VERSION 5.7 ;
  NOWIREEXTENSIONATPIN ON ;
  DIVIDERCHAR "/" ;
  BUSBITCHARS "[]" ;
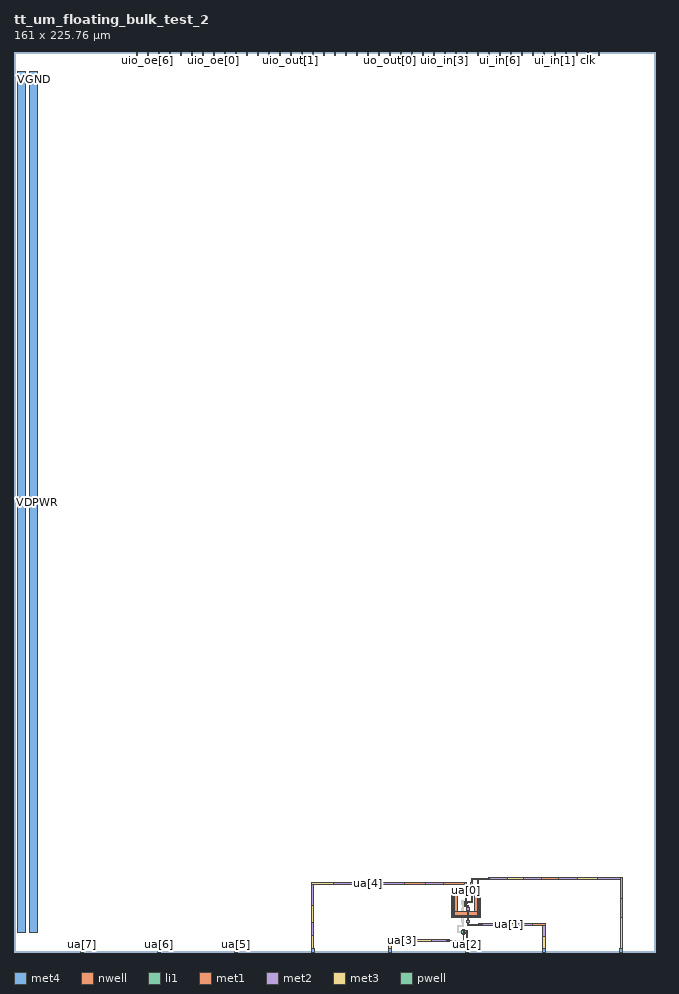
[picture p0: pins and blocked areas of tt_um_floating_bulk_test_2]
MACRO tt_um_floating_bulk_test_2
  CLASS BLOCK ;
  FOREIGN tt_um_floating_bulk_test_2 ;
  ORIGIN 0.000 0.000 ;
  SIZE 161.000 BY 225.760 ;
  PIN clk
    DIRECTION INPUT ;
    USE SIGNAL ;
    PORT
      LAYER met4 ;
        RECT 143.830 224.760 144.130 225.760 ;
    END
  END clk
  PIN ena
    DIRECTION INPUT ;
    USE SIGNAL ;
    PORT
      LAYER met4 ;
        RECT 146.590 224.760 146.890 225.760 ;
    END
  END ena
  PIN rst_n
    DIRECTION INPUT ;
    USE SIGNAL ;
    PORT
      LAYER met4 ;
        RECT 141.070 224.760 141.370 225.760 ;
    END
  END rst_n
  PIN ua[0]
    DIRECTION INOUT ;
    USE SIGNAL ;
    ANTENNADIFFAREA 9.653000 ;
    PORT
      LAYER nwell ;
        RECT 109.860 14.600 116.910 16.030 ;
        RECT 109.860 10.150 111.290 14.600 ;
        RECT 115.480 10.150 116.910 14.600 ;
        RECT 109.860 8.720 116.910 10.150 ;
      LAYER li1 ;
        RECT 111.570 15.745 115.140 15.760 ;
        RECT 110.145 15.575 116.625 15.745 ;
        RECT 110.145 14.770 110.315 15.575 ;
        RECT 111.570 15.570 115.140 15.575 ;
        RECT 110.140 9.900 110.320 14.770 ;
        RECT 116.455 14.660 116.625 15.575 ;
        RECT 113.445 12.195 113.615 12.655 ;
        RECT 116.450 10.160 116.640 14.660 ;
        RECT 110.145 9.175 110.315 9.900 ;
        RECT 111.260 9.175 115.570 9.180 ;
        RECT 116.455 9.175 116.625 10.160 ;
        RECT 110.145 9.005 116.625 9.175 ;
        RECT 111.260 8.990 115.570 9.005 ;
      LAYER met1 ;
        RECT 118.950 18.500 119.400 18.600 ;
        RECT 114.750 18.250 119.400 18.500 ;
        RECT 114.760 17.360 115.000 18.250 ;
        RECT 114.630 16.840 115.130 17.360 ;
        RECT 116.250 15.820 116.500 18.250 ;
        RECT 118.950 18.150 119.400 18.250 ;
        RECT 131.650 18.100 137.250 18.650 ;
        RECT 110.060 15.490 116.710 15.820 ;
        RECT 110.060 9.260 110.410 15.490 ;
        RECT 114.640 13.800 115.130 14.290 ;
        RECT 114.810 12.640 114.950 13.800 ;
        RECT 113.410 12.500 114.950 12.640 ;
        RECT 113.410 12.210 113.650 12.500 ;
        RECT 116.370 9.260 116.710 15.490 ;
        RECT 152.100 13.500 152.650 18.650 ;
        RECT 110.060 8.920 116.710 9.260 ;
      LAYER met2 ;
        RECT 123.150 18.600 123.700 18.650 ;
        RECT 118.950 18.150 123.700 18.600 ;
        RECT 123.150 18.100 123.700 18.150 ;
        RECT 127.300 18.100 132.200 18.650 ;
        RECT 136.700 18.100 141.800 18.650 ;
        RECT 145.700 18.100 152.650 18.650 ;
        RECT 114.630 16.840 115.130 17.360 ;
        RECT 114.730 14.290 115.030 16.840 ;
        RECT 114.640 13.800 115.130 14.290 ;
        RECT 152.100 8.750 152.650 14.050 ;
      LAYER met3 ;
        RECT 123.150 18.100 127.850 18.650 ;
        RECT 141.250 18.100 146.250 18.650 ;
        RECT 152.100 0.250 152.650 9.300 ;
      LAYER met4 ;
        RECT 151.810 0.000 152.710 1.000 ;
    END
  END ua[0]
  PIN ua[1]
    DIRECTION INOUT ;
    USE SIGNAL ;
    ANTENNADIFFAREA 0.121800 ;
    PORT
      LAYER li1 ;
        RECT 113.005 12.195 113.175 12.655 ;
      LAYER met1 ;
        RECT 112.970 11.610 113.210 12.640 ;
        RECT 112.970 11.370 113.990 11.610 ;
        RECT 113.750 11.040 113.990 11.370 ;
        RECT 113.600 10.470 114.140 11.040 ;
        RECT 113.630 7.380 114.140 7.880 ;
        RECT 113.710 7.015 114.040 7.380 ;
        RECT 116.500 7.015 117.600 7.100 ;
        RECT 113.710 6.685 117.600 7.015 ;
        RECT 116.500 6.550 117.600 6.685 ;
        RECT 129.950 6.550 133.200 7.100 ;
      LAYER met2 ;
        RECT 113.600 10.470 114.140 11.040 ;
        RECT 113.710 7.880 114.030 10.470 ;
        RECT 113.630 7.380 114.140 7.880 ;
        RECT 117.050 6.550 122.050 7.100 ;
        RECT 126.050 6.550 130.500 7.100 ;
        RECT 132.650 3.350 133.200 7.100 ;
      LAYER met3 ;
        RECT 121.500 6.550 126.600 7.100 ;
        RECT 132.650 0.200 133.200 3.900 ;
      LAYER met4 ;
        RECT 132.490 0.000 133.390 1.000 ;
    END
  END ua[1]
  PIN ua[2]
    DIRECTION INOUT ;
    USE SIGNAL ;
    ANTENNADIFFAREA 0.220800 ;
    PORT
      LAYER pwell ;
        RECT 113.280 5.405 113.720 5.480 ;
        RECT 112.265 4.725 113.720 5.405 ;
        RECT 113.280 4.670 113.720 4.725 ;
      LAYER li1 ;
        RECT 112.895 4.835 113.065 5.295 ;
        RECT 113.410 4.840 113.590 5.310 ;
      LAYER met1 ;
        RECT 113.325 5.280 113.660 5.500 ;
        RECT 112.860 4.850 113.660 5.280 ;
        RECT 113.350 4.840 113.660 4.850 ;
        RECT 113.470 2.500 113.660 4.840 ;
        RECT 113.350 1.700 113.800 2.500 ;
      LAYER met2 ;
        RECT 113.300 1.650 113.850 2.200 ;
      LAYER met3 ;
        RECT 113.300 0.250 113.850 2.200 ;
      LAYER met4 ;
        RECT 113.170 0.000 114.070 1.000 ;
    END
  END ua[2]
  PIN ua[3]
    DIRECTION INOUT ;
    USE SIGNAL ;
    ANTENNAGATEAREA 0.063000 ;
    PORT
      LAYER li1 ;
        RECT 112.595 5.465 112.925 5.635 ;
        RECT 112.595 4.495 112.925 4.665 ;
      LAYER met1 ;
        RECT 112.590 5.430 112.930 5.750 ;
        RECT 112.590 4.380 112.930 4.700 ;
        RECT 108.500 2.980 109.350 3.100 ;
        RECT 112.670 2.980 112.840 4.380 ;
        RECT 108.500 2.825 112.840 2.980 ;
        RECT 108.500 2.650 109.350 2.825 ;
        RECT 112.670 2.815 112.840 2.825 ;
      LAYER met2 ;
        RECT 94.050 2.600 100.450 3.150 ;
        RECT 104.700 3.100 105.250 3.150 ;
        RECT 104.700 2.650 108.950 3.100 ;
        RECT 104.700 2.600 105.250 2.650 ;
      LAYER met3 ;
        RECT 94.050 0.250 94.600 3.150 ;
        RECT 99.900 2.600 105.250 3.150 ;
      LAYER met4 ;
        RECT 93.850 0.000 94.750 1.000 ;
    END
  END ua[3]
  PIN ua[4]
    DIRECTION INOUT ;
    USE SIGNAL ;
    ANTENNAGATEAREA 0.063000 ;
    PORT
      LAYER li1 ;
        RECT 113.145 12.825 113.475 12.995 ;
        RECT 113.145 11.855 113.475 12.025 ;
      LAYER met1 ;
        RECT 85.250 16.900 92.150 17.450 ;
        RECT 97.950 16.900 103.700 17.450 ;
        RECT 107.750 17.370 108.850 17.450 ;
        RECT 113.080 17.370 113.560 17.470 ;
        RECT 107.750 17.040 113.560 17.370 ;
        RECT 107.750 16.900 108.850 17.040 ;
        RECT 113.080 16.960 113.560 17.040 ;
        RECT 113.070 13.910 113.570 14.410 ;
        RECT 113.220 13.110 113.400 13.910 ;
        RECT 113.140 12.790 113.480 13.110 ;
      LAYER met2 ;
        RECT 74.700 11.000 75.250 17.450 ;
        RECT 79.500 16.900 85.800 17.450 ;
        RECT 91.600 16.900 98.500 17.450 ;
        RECT 103.150 16.900 108.300 17.450 ;
        RECT 113.080 16.960 113.560 17.470 ;
        RECT 113.150 14.410 113.480 16.960 ;
        RECT 113.070 13.910 113.570 14.410 ;
        RECT 74.700 3.550 75.250 7.900 ;
      LAYER met3 ;
        RECT 74.700 16.900 80.050 17.450 ;
        RECT 74.700 7.350 75.250 11.550 ;
        RECT 74.700 0.250 75.250 4.100 ;
      LAYER met4 ;
        RECT 74.530 0.000 75.430 1.000 ;
    END
  END ua[4]
  PIN ua[5]
    DIRECTION INOUT ;
    USE SIGNAL ;
    PORT
      LAYER met4 ;
        RECT 55.210 0.000 56.110 1.000 ;
    END
  END ua[5]
  PIN ua[6]
    DIRECTION INOUT ;
    USE SIGNAL ;
    PORT
      LAYER met4 ;
        RECT 35.890 0.000 36.790 1.000 ;
    END
  END ua[6]
  PIN ua[7]
    DIRECTION INOUT ;
    USE SIGNAL ;
    PORT
      LAYER met4 ;
        RECT 16.570 0.000 17.470 1.000 ;
    END
  END ua[7]
  PIN ui_in[0]
    DIRECTION INPUT ;
    USE SIGNAL ;
    PORT
      LAYER met4 ;
        RECT 138.310 224.760 138.610 225.760 ;
    END
  END ui_in[0]
  PIN ui_in[1]
    DIRECTION INPUT ;
    USE SIGNAL ;
    PORT
      LAYER met4 ;
        RECT 135.550 224.760 135.850 225.760 ;
    END
  END ui_in[1]
  PIN ui_in[2]
    DIRECTION INPUT ;
    USE SIGNAL ;
    PORT
      LAYER met4 ;
        RECT 132.790 224.760 133.090 225.760 ;
    END
  END ui_in[2]
  PIN ui_in[3]
    DIRECTION INPUT ;
    USE SIGNAL ;
    PORT
      LAYER met4 ;
        RECT 130.030 224.760 130.330 225.760 ;
    END
  END ui_in[3]
  PIN ui_in[4]
    DIRECTION INPUT ;
    USE SIGNAL ;
    PORT
      LAYER met4 ;
        RECT 127.270 224.760 127.570 225.760 ;
    END
  END ui_in[4]
  PIN ui_in[5]
    DIRECTION INPUT ;
    USE SIGNAL ;
    PORT
      LAYER met4 ;
        RECT 124.510 224.760 124.810 225.760 ;
    END
  END ui_in[5]
  PIN ui_in[6]
    DIRECTION INPUT ;
    USE SIGNAL ;
    PORT
      LAYER met4 ;
        RECT 121.750 224.760 122.050 225.760 ;
    END
  END ui_in[6]
  PIN ui_in[7]
    DIRECTION INPUT ;
    USE SIGNAL ;
    PORT
      LAYER met4 ;
        RECT 118.990 224.760 119.290 225.760 ;
    END
  END ui_in[7]
  PIN uio_in[0]
    DIRECTION INPUT ;
    USE SIGNAL ;
    PORT
      LAYER met4 ;
        RECT 116.230 224.760 116.530 225.760 ;
    END
  END uio_in[0]
  PIN uio_in[1]
    DIRECTION INPUT ;
    USE SIGNAL ;
    PORT
      LAYER met4 ;
        RECT 113.470 224.760 113.770 225.760 ;
    END
  END uio_in[1]
  PIN uio_in[2]
    DIRECTION INPUT ;
    USE SIGNAL ;
    PORT
      LAYER met4 ;
        RECT 110.710 224.760 111.010 225.760 ;
    END
  END uio_in[2]
  PIN uio_in[3]
    DIRECTION INPUT ;
    USE SIGNAL ;
    PORT
      LAYER met4 ;
        RECT 107.950 224.760 108.250 225.760 ;
    END
  END uio_in[3]
  PIN uio_in[4]
    DIRECTION INPUT ;
    USE SIGNAL ;
    PORT
      LAYER met4 ;
        RECT 105.190 224.760 105.490 225.760 ;
    END
  END uio_in[4]
  PIN uio_in[5]
    DIRECTION INPUT ;
    USE SIGNAL ;
    PORT
      LAYER met4 ;
        RECT 102.430 224.760 102.730 225.760 ;
    END
  END uio_in[5]
  PIN uio_in[6]
    DIRECTION INPUT ;
    USE SIGNAL ;
    PORT
      LAYER met4 ;
        RECT 99.670 224.760 99.970 225.760 ;
    END
  END uio_in[6]
  PIN uio_in[7]
    DIRECTION INPUT ;
    USE SIGNAL ;
    PORT
      LAYER met4 ;
        RECT 96.910 224.760 97.210 225.760 ;
    END
  END uio_in[7]
  PIN uio_oe[0]
    DIRECTION OUTPUT ;
    USE SIGNAL ;
    PORT
      LAYER met4 ;
        RECT 49.990 224.760 50.290 225.760 ;
    END
  END uio_oe[0]
  PIN uio_oe[1]
    DIRECTION OUTPUT ;
    USE SIGNAL ;
    PORT
      LAYER met4 ;
        RECT 47.230 224.760 47.530 225.760 ;
    END
  END uio_oe[1]
  PIN uio_oe[2]
    DIRECTION OUTPUT ;
    USE SIGNAL ;
    PORT
      LAYER met4 ;
        RECT 44.470 224.760 44.770 225.760 ;
    END
  END uio_oe[2]
  PIN uio_oe[3]
    DIRECTION OUTPUT ;
    USE SIGNAL ;
    PORT
      LAYER met4 ;
        RECT 41.710 224.760 42.010 225.760 ;
    END
  END uio_oe[3]
  PIN uio_oe[4]
    DIRECTION OUTPUT ;
    USE SIGNAL ;
    PORT
      LAYER met4 ;
        RECT 38.950 224.760 39.250 225.760 ;
    END
  END uio_oe[4]
  PIN uio_oe[5]
    DIRECTION OUTPUT ;
    USE SIGNAL ;
    PORT
      LAYER met4 ;
        RECT 36.190 224.760 36.490 225.760 ;
    END
  END uio_oe[5]
  PIN uio_oe[6]
    DIRECTION OUTPUT ;
    USE SIGNAL ;
    PORT
      LAYER met4 ;
        RECT 33.430 224.760 33.730 225.760 ;
    END
  END uio_oe[6]
  PIN uio_oe[7]
    DIRECTION OUTPUT ;
    USE SIGNAL ;
    PORT
      LAYER met4 ;
        RECT 30.670 224.760 30.970 225.760 ;
    END
  END uio_oe[7]
  PIN uio_out[0]
    DIRECTION OUTPUT ;
    USE SIGNAL ;
    PORT
      LAYER met4 ;
        RECT 72.070 224.760 72.370 225.760 ;
    END
  END uio_out[0]
  PIN uio_out[1]
    DIRECTION OUTPUT ;
    USE SIGNAL ;
    PORT
      LAYER met4 ;
        RECT 69.310 224.760 69.610 225.760 ;
    END
  END uio_out[1]
  PIN uio_out[2]
    DIRECTION OUTPUT ;
    USE SIGNAL ;
    PORT
      LAYER met4 ;
        RECT 66.550 224.760 66.850 225.760 ;
    END
  END uio_out[2]
  PIN uio_out[3]
    DIRECTION OUTPUT ;
    USE SIGNAL ;
    PORT
      LAYER met4 ;
        RECT 63.790 224.760 64.090 225.760 ;
    END
  END uio_out[3]
  PIN uio_out[4]
    DIRECTION OUTPUT ;
    USE SIGNAL ;
    PORT
      LAYER met4 ;
        RECT 61.030 224.760 61.330 225.760 ;
    END
  END uio_out[4]
  PIN uio_out[5]
    DIRECTION OUTPUT ;
    USE SIGNAL ;
    PORT
      LAYER met4 ;
        RECT 58.270 224.760 58.570 225.760 ;
    END
  END uio_out[5]
  PIN uio_out[6]
    DIRECTION OUTPUT ;
    USE SIGNAL ;
    PORT
      LAYER met4 ;
        RECT 55.510 224.760 55.810 225.760 ;
    END
  END uio_out[6]
  PIN uio_out[7]
    DIRECTION OUTPUT ;
    USE SIGNAL ;
    PORT
      LAYER met4 ;
        RECT 52.750 224.760 53.050 225.760 ;
    END
  END uio_out[7]
  PIN uo_out[0]
    DIRECTION OUTPUT ;
    USE SIGNAL ;
    PORT
      LAYER met4 ;
        RECT 94.150 224.760 94.450 225.760 ;
    END
  END uo_out[0]
  PIN uo_out[1]
    DIRECTION OUTPUT ;
    USE SIGNAL ;
    PORT
      LAYER met4 ;
        RECT 91.390 224.760 91.690 225.760 ;
    END
  END uo_out[1]
  PIN uo_out[2]
    DIRECTION OUTPUT ;
    USE SIGNAL ;
    PORT
      LAYER met4 ;
        RECT 88.630 224.760 88.930 225.760 ;
    END
  END uo_out[2]
  PIN uo_out[3]
    DIRECTION OUTPUT ;
    USE SIGNAL ;
    PORT
      LAYER met4 ;
        RECT 85.870 224.760 86.170 225.760 ;
    END
  END uo_out[3]
  PIN uo_out[4]
    DIRECTION OUTPUT ;
    USE SIGNAL ;
    PORT
      LAYER met4 ;
        RECT 83.110 224.760 83.410 225.760 ;
    END
  END uo_out[4]
  PIN uo_out[5]
    DIRECTION OUTPUT ;
    USE SIGNAL ;
    PORT
      LAYER met4 ;
        RECT 80.350 224.760 80.650 225.760 ;
    END
  END uo_out[5]
  PIN uo_out[6]
    DIRECTION OUTPUT ;
    USE SIGNAL ;
    PORT
      LAYER met4 ;
        RECT 77.590 224.760 77.890 225.760 ;
    END
  END uo_out[6]
  PIN uo_out[7]
    DIRECTION OUTPUT ;
    USE SIGNAL ;
    PORT
      LAYER met4 ;
        RECT 74.830 224.760 75.130 225.760 ;
    END
  END uo_out[7]
  PIN VDPWR
    DIRECTION INOUT ;
    USE POWER ;
    PORT
      LAYER met4 ;
        RECT 1.000 5.000 3.000 220.760 ;
    END
  END VDPWR
  PIN VGND
    DIRECTION INOUT ;
    USE GROUND ;
    PORT
      LAYER met4 ;
        RECT 4.000 5.000 6.000 220.760 ;
    END
  END VGND
  OBS
      LAYER pwell ;
        RECT 112.330 12.765 112.770 12.820 ;
        RECT 112.330 12.085 113.805 12.765 ;
        RECT 112.330 12.010 112.770 12.085 ;
      LAYER li1 ;
        RECT 112.460 12.180 112.640 12.650 ;
        RECT 112.455 4.835 112.625 5.295 ;
      LAYER met1 ;
        RECT 112.400 12.180 112.710 12.650 ;
        RECT 112.460 10.950 112.640 12.180 ;
        RECT 112.280 10.380 112.820 10.950 ;
        RECT 112.290 7.350 112.750 7.800 ;
        RECT 112.380 6.640 112.660 7.350 ;
        RECT 111.310 6.360 112.660 6.640 ;
        RECT 111.310 5.230 111.590 6.360 ;
        RECT 112.425 5.230 112.655 5.275 ;
        RECT 111.310 4.950 112.655 5.230 ;
        RECT 112.425 4.855 112.655 4.950 ;
      LAYER met2 ;
        RECT 112.280 10.380 112.820 10.950 ;
        RECT 112.360 10.120 112.730 10.380 ;
        RECT 112.360 7.800 112.700 10.120 ;
        RECT 112.290 7.350 112.750 7.800 ;
  END
END tt_um_floating_bulk_test_2
END LIBRARY

